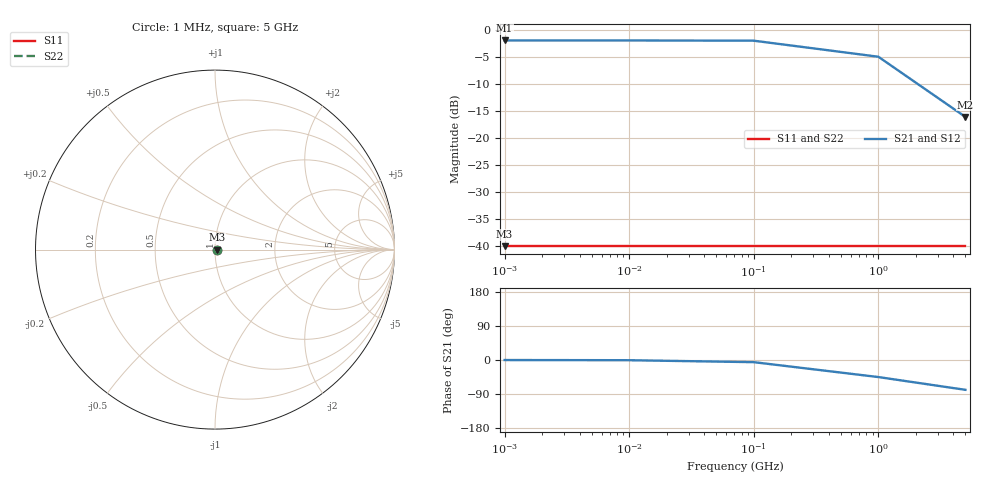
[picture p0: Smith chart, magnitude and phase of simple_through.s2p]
! Agent-Spice simple passive 2-port fixture for VectorFitting smoke tests.
# Hz S RI R 50
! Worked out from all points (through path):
!   5 points, 1 MHz to 5 GHz, reference 50 ohm
!   highest |S21| = -1.94 dB at 1 MHz (marker M1); lowest = -16.1 dB at 5 GHz (marker M2)
!   lowest |S11| = -40.0 dB at 1 MHz (marker M3), VSWR 1.02, Z = 51 + j0 ohm
!   |S11| at or under -10 dB: start of sweep to end of sweep
!   |S22| runs from -40.0 to -40.0 dB; largest |S21 - S12| = 0
1000000  0.01 0  0.8 -0.0008  0.8 -0.0008  0.01 0
1e7  0.01 0  0.7999 -0.008  0.7999 -0.008  0.01 0
1e8  0.01 0  0.7921 -0.0792  0.7921 -0.0792  0.01 0
1e9  0.01 0  0.4 -0.4  0.4 -0.4  0.01 0
5e9  0.01 0  0.0308 -0.1538  0.0308 -0.1538  0.01 0
